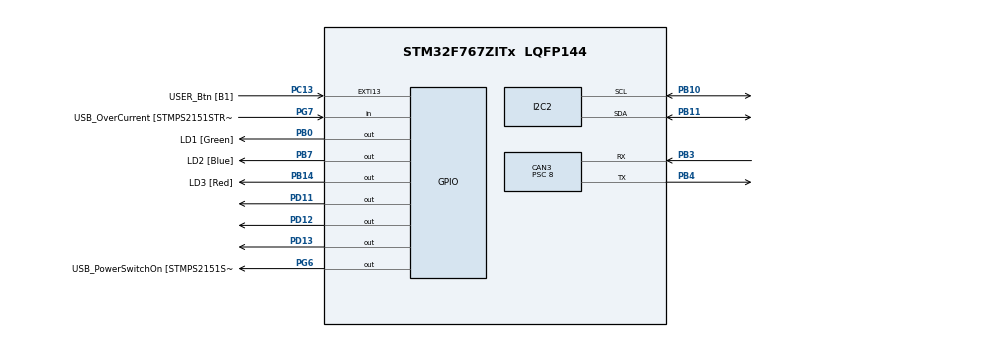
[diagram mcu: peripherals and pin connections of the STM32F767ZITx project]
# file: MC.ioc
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CAN3.BS1=CAN_BS1_5TQ
CAN3.BS2=CAN_BS2_6TQ
CAN3.CalculateBaudRate=500000
CAN3.CalculateTimeBit=2000
CAN3.CalculateTimeQuantum=166.66666666666666
CAN3.Prescaler=8
I2C2.Timing=0x20303E5D
Mcu.Family=STM32F7
Mcu.Name=STM32F767ZITx
Mcu.Package=LQFP144
NVIC.PriorityGroup=NVIC_PRIORITYGROUP_4
PA1.GPIO_Label=RMII_REF_CLK [LAN8742A-CZ-TR_REFCLK0]
PA1.Signal=ETH_REF_CLK
PA10.GPIO_Label=USB_ID
PA10.Signal=USB_OTG_FS_ID
PA11.GPIO_Label=USB_DM
PA11.Signal=USB_OTG_FS_DM
PA12.GPIO_Label=USB_DP
PA12.Signal=USB_OTG_FS_DP
PA13.GPIO_Label=TMS
PA13.Mode=Serial_Wire
PA13.Signal=SYS_JTMS-SWDIO
PA14.GPIO_Label=TCK
PA14.Mode=Serial_Wire
PA14.Signal=SYS_JTCK-SWCLK
PA2.GPIO_Label=RMII_MDIO [LAN8742A-CZ-TR_MDIO]
PA2.Signal=ETH_MDIO
PA7.GPIO_Label=RMII_CRS_DV [LAN8742A-CZ-TR_CRS_DV]
PA7.Signal=ETH_CRS_DV
PA8.GPIO_Label=USB_SOF [TP1]
PA8.Signal=USB_OTG_FS_SOF
PA9.GPIO_Label=USB_VBUS
PA9.Signal=USB_OTG_FS_VBUS
PB0.GPIO_Label=LD1 [Green]
PB0.Signal=GPIO_Output
PB10.Mode=I2C
PB10.Signal=I2C2_SCL
PB11.Mode=I2C
PB11.Signal=I2C2_SDA
PB13.GPIO_Label=RMII_TXD1 [LAN8742A-CZ-TR_TXD1]
PB13.Signal=ETH_TXD1
PB14.GPIO_Label=LD3 [Red]
PB14.Signal=GPIO_Output
PB3.Mode=CAN_Activate
PB3.Signal=CAN3_RX
PB4.Mode=CAN_Activate
PB4.Signal=CAN3_TX
PB7.GPIO_Label=LD2 [Blue]
PB7.Signal=GPIO_Output
PC1.GPIO_Label=RMII_MDC [LAN8742A-CZ-TR_MDC]
PC1.Signal=ETH_MDC
PC13.GPIO_Label=USER_Btn [B1]
PC13.Signal=GPXTI13
PC14/OSC32_IN.Mode=LSE-External-Oscillator
PC14/OSC32_IN.Signal=RCC_OSC32_IN
PC15/OSC32_OUT.Mode=LSE-External-Oscillator
PC15/OSC32_OUT.Signal=RCC_OSC32_OUT
PC4.GPIO_Label=RMII_RXD0 [LAN8742A-CZ-TR_RXD0]
PC4.Signal=ETH_RXD0
PC5.GPIO_Label=RMII_RXD1 [LAN8742A-CZ-TR_RXD1]
PC5.Signal=ETH_RXD1
PD11.Signal=GPIO_Output
PD12.Signal=GPIO_Output
PD13.Signal=GPIO_Output
PD8.GPIO_Label=STLK_RX [STM32F103CBT6_PA3]
PD8.Signal=USART3_TX
PD9.GPIO_Label=STLK_TX [STM32F103CBT6_PA2]
PD9.Signal=USART3_RX
PG11.GPIO_Label=RMII_TX_EN [LAN8742A-CZ-TR_TXEN]
PG11.Signal=ETH_TX_EN
PG13.GPIO_Label=RMII_TXD0 [LAN8742A-CZ-TR_TXD0]
PG13.Signal=ETH_TXD0
PG6.GPIO_Label=USB_PowerSwitchOn [STMPS2151STR_EN]
PG6.Signal=GPIO_Output
PG7.GPIO_Label=USB_OverCurrent [STMPS2151STR_FAULT]
PG7.Signal=GPIO_Input
PH0/OSC_IN.GPIO_Label=MCO [STM32F103CBT6_PA8]
PH0/OSC_IN.Mode=HSE-External-Clock-Source
PH0/OSC_IN.Signal=RCC_OSC_IN
PH1/OSC_OUT.Mode=HSE-External-Clock-Source
PH1/OSC_OUT.Signal=RCC_OSC_OUT
ProjectManager.HeapSize=0x200
ProjectManager.StackSize=0x400
ProjectManager.TargetToolchain=STM32CubeIDE
RCC.48MHZClocksFreq_Value=24000000
RCC.AHBFreq_Value=96000000
RCC.APB1CLKDivider=RCC_HCLK_DIV2
RCC.APB1Freq_Value=48000000
RCC.APB1TimFreq_Value=96000000
RCC.APB2Freq_Value=96000000
RCC.APB2TimFreq_Value=96000000
RCC.CortexFreq_Value=96000000
RCC.HCLKFreq_Value=96000000
RCC.HSE_VALUE=8000000
RCC.HSI_VALUE=16000000
RCC.PLLM=4
RCC.PLLMUL=RCC_PLL_MUL9
RCC.PLLN=96
RCC.PLLQ=4
RCC.PLLSourceVirtual=RCC_PLLSOURCE_HSE
RCC.PRESCALERUSB=RCC_USBCLKSOURCE_PLL_DIV1_5
RCC.SYSCLKFreq_VALUE=96000000
RCC.SYSCLKSource=RCC_SYSCLKSOURCE_PLLCLK
RCC.SYSCLKSourceVirtual=RCC_SYSCLKSOURCE_PLLCLK
RCC.USBFreq_Value=48000000
RCC.VCOOutputFreq_Value=192000000
board=NUCLEO-F767ZI

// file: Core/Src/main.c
/* USER CODE BEGIN Header */
/**
  ******************************************************************************
  * @file           : main.c
  * @brief          : Main program body
  ******************************************************************************
  * @attention
  *
  * Copyright (c) 2024 STMicroelectronics.
  * All rights reserved.
  *
  * This software is licensed under terms that can be found in the LICENSE file
  * in the root directory of this software component.
  * If no LICENSE file comes with this software, it is provided AS-IS.
  *
  ******************************************************************************
  */
/* USER CODE END Header */
#include "main.h"
#include "can.h"
#include "i2c.h"
#include "gpio.h"

/* USER CODE BEGIN Includes */
#include "motor_controller.h"
/* USER CODE END Includes */

void SystemClock_Config(void);

int main(void)
{

  /* MCU Configuration--------------------------------------------------------*/

  /* Reset of all peripherals, Initializes the Flash interface and the Systick. */
  HAL_Init();

  /* Configure the system clock */
  SystemClock_Config();

  /* Initialize all configured peripherals */
  MX_GPIO_Init();
  MX_I2C2_Init();
  MX_CAN3_Init();
  /* USER CODE BEGIN 2 */
  HAL_CAN_Start(&hcan3);

  Motor_Controller_t data_struct = MC_init(&hcan3, &hi2c2);
  CAN_Frame_t tx_frame = CAN_frame_init(&hcan3, 0xFFFFFFFF);
  /* USER CODE END 2 */

  /* Infinite loop */
  /* USER CODE BEGIN WHILE */
  while (1)
  {
	while (HAL_CAN_GetRxFifoFillLevel(&hcan3, CAN_RX_FIFO1)) {
		MC_execute_command(CAN_get_frame(&hcan3, CAN_RX_FIFO1));
	}

	if (HAL_CAN_GetTxMailboxesFreeLevel(&hcan3)) {
		MC_get_data(&data_struct);
	}

	//build tx_frame here
	//...

	CAN_send_frame(tx_frame);
	HAL_Delay(50);
    /* USER CODE END WHILE */

  }
}

void SystemClock_Config(void)
{
  RCC_OscInitTypeDef RCC_OscInitStruct = {0};
  RCC_ClkInitTypeDef RCC_ClkInitStruct = {0};

  /** Configure LSE Drive Capability
  */
  HAL_PWR_EnableBkUpAccess();

  /** Configure the main internal regulator output voltage
  */
  __HAL_RCC_PWR_CLK_ENABLE();
  __HAL_PWR_VOLTAGESCALING_CONFIG(PWR_REGULATOR_VOLTAGE_SCALE3);

  /** Initializes the RCC Oscillators according to the specified parameters
  * in the RCC_OscInitTypeDef structure.
  */
  RCC_OscInitStruct.OscillatorType = RCC_OSCILLATORTYPE_HSE;
  RCC_OscInitStruct.HSEState = RCC_HSE_BYPASS;
  RCC_OscInitStruct.PLL.PLLState = RCC_PLL_ON;
  RCC_OscInitStruct.PLL.PLLSource = RCC_PLLSOURCE_HSE;
  RCC_OscInitStruct.PLL.PLLM = 4;
  RCC_OscInitStruct.PLL.PLLN = 96;
  RCC_OscInitStruct.PLL.PLLP = RCC_PLLP_DIV6;
  RCC_OscInitStruct.PLL.PLLQ = 4;
  RCC_OscInitStruct.PLL.PLLR = 2;
  if (HAL_RCC_OscConfig(&RCC_OscInitStruct) != HAL_OK)
  {
    Error_Handler();
  }

  /** Initializes the CPU, AHB and APB buses clocks
  */
  RCC_ClkInitStruct.ClockType = RCC_CLOCKTYPE_HCLK|RCC_CLOCKTYPE_SYSCLK
                              |RCC_CLOCKTYPE_PCLK1|RCC_CLOCKTYPE_PCLK2;
  RCC_ClkInitStruct.SYSCLKSource = RCC_SYSCLKSOURCE_PLLCLK;
  RCC_ClkInitStruct.AHBCLKDivider = RCC_SYSCLK_DIV2;
  RCC_ClkInitStruct.APB1CLKDivider = RCC_HCLK_DIV2;
  RCC_ClkInitStruct.APB2CLKDivider = RCC_HCLK_DIV1;

  if (HAL_RCC_ClockConfig(&RCC_ClkInitStruct, FLASH_LATENCY_0) != HAL_OK)
  {
    Error_Handler();
  }
}

void Error_Handler(void)
{
  __disable_irq();
  while (1)
  {
  }
}
